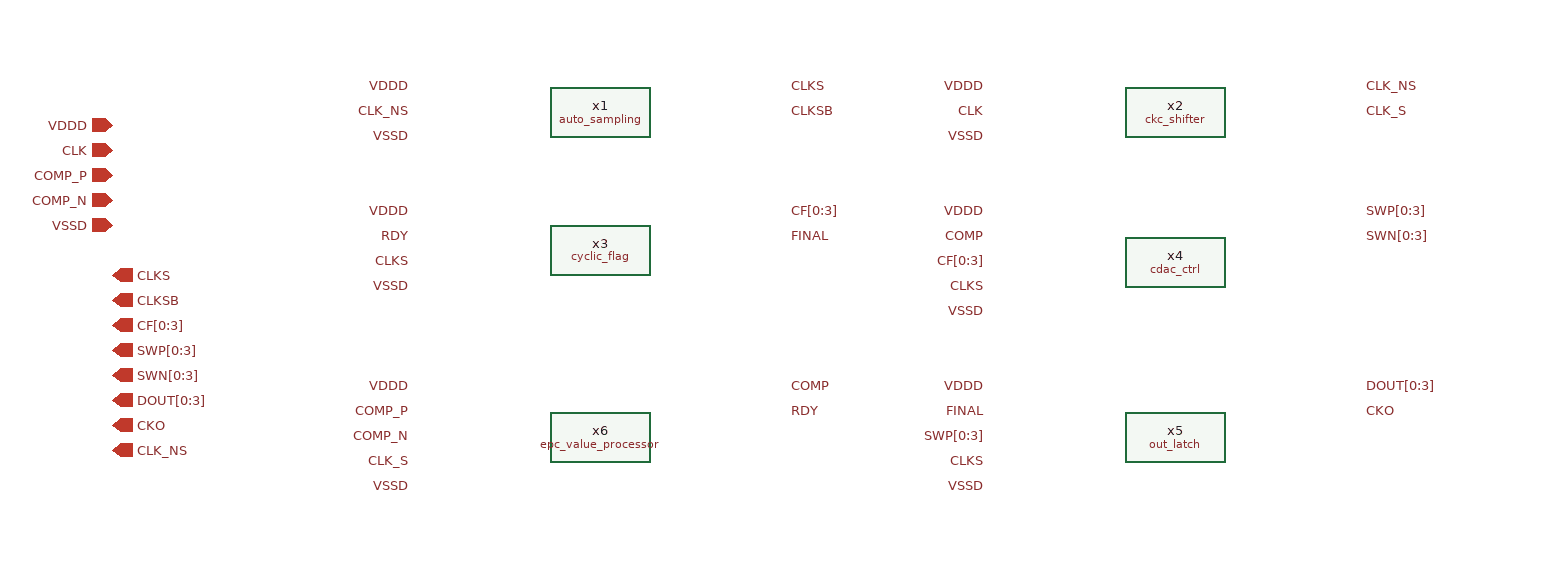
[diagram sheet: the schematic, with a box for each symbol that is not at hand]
v {xschem version=3.4.5 file_version=1.2
}
G {}
K {}
V {}
S {}
E {}
C {ckc_shifter.sym} 990 -390 0 0 {name=x2}
C {cyclic_flag.sym} 530 -280 0 0 {name=x3}
C {cdac_ctrl.sym} 990 -270 0 0 {name=x4}
C {out_latch.sym} 990 -130 0 0 {name=x5}
C {epc_value_processor.sym} 530 -130 0 0 {name=x6}
C {devices/ipin.sym} 140 -380 0 0 {name=p20 sig_type=std_logic lab=VDDD}
C {devices/ipin.sym} 140 -300 0 0 {name=p22 sig_type=std_logic lab=VSSD}
C {devices/lab_wire.sym} 380 -410 0 0 {name=p5 sig_type=std_logic lab=VDDD}
C {devices/lab_wire.sym} 380 -310 0 0 {name=p1 sig_type=std_logic lab=VDDD}
C {devices/lab_wire.sym} 380 -170 0 0 {name=p2 sig_type=std_logic lab=VDDD}
C {devices/lab_wire.sym} 840 -170 0 0 {name=p3 sig_type=std_logic lab=VDDD}
C {devices/lab_wire.sym} 840 -310 0 0 {name=p4 sig_type=std_logic lab=VDDD}
C {devices/lab_wire.sym} 840 -410 0 0 {name=p6 sig_type=std_logic lab=VDDD}
C {devices/lab_wire.sym} 380 -370 0 0 {name=p8 sig_type=std_logic lab=VSSD}
C {devices/lab_wire.sym} 380 -250 0 0 {name=p10 sig_type=std_logic lab=VSSD}
C {devices/lab_wire.sym} 380 -90 0 0 {name=p11 sig_type=std_logic lab=VSSD}
C {devices/lab_wire.sym} 840 -90 0 0 {name=p12 sig_type=std_logic lab=VSSD}
C {devices/lab_wire.sym} 840 -230 0 0 {name=p13 sig_type=std_logic lab=VSSD}
C {devices/lab_wire.sym} 840 -370 0 0 {name=p14 sig_type=std_logic lab=VSSD}
C {devices/lab_wire.sym} 380 -390 0 0 {name=p15 sig_type=std_logic lab=CLK_NS}
C {devices/lab_wire.sym} 1140 -410 0 1 {name=p16 sig_type=std_logic lab=CLK_NS}
C {devices/lab_wire.sym} 1140 -390 0 1 {name=p17 sig_type=std_logic lab=CLK_S}
C {devices/lab_wire.sym} 380 -110 0 0 {name=p18 sig_type=std_logic lab=CLK_S}
C {devices/lab_wire.sym} 840 -390 0 0 {name=p21 sig_type=std_logic lab=CLK}
C {devices/lab_wire.sym} 380 -150 0 0 {name=p25 sig_type=std_logic lab=COMP_P}
C {devices/lab_wire.sym} 380 -130 0 0 {name=p26 sig_type=std_logic lab=COMP_N}
C {devices/lab_wire.sym} 680 -170 0 1 {name=p27 sig_type=std_logic lab=COMP}
C {devices/lab_wire.sym} 680 -150 0 1 {name=p28 sig_type=std_logic lab=RDY}
C {devices/lab_wire.sym} 380 -290 0 0 {name=p29 sig_type=std_logic lab=RDY}
C {devices/lab_wire.sym} 380 -270 0 0 {name=p30 sig_type=std_logic lab=CLKS}
C {devices/lab_wire.sym} 680 -410 0 1 {name=p31 sig_type=std_logic lab=CLKS}
C {auto_sampling.sym} 530 -390 0 0 {name=x1}
C {devices/lab_wire.sym} 840 -250 0 0 {name=p32 sig_type=std_logic lab=CLKS}
C {devices/lab_wire.sym} 840 -110 0 0 {name=p33 sig_type=std_logic lab=CLKS}
C {devices/lab_wire.sym} 680 -290 0 1 {name=p34 sig_type=std_logic lab=FINAL}
C {devices/lab_wire.sym} 840 -150 0 0 {name=p35 sig_type=std_logic lab=FINAL}
C {devices/lab_wire.sym} 840 -290 0 0 {name=p36 sig_type=std_logic lab=COMP}
C {devices/lab_wire.sym} 680 -310 0 1 {name=p37 sig_type=std_logic lab=CF[0:3]}
C {devices/lab_wire.sym} 840 -270 0 0 {name=p38 sig_type=std_logic lab=CF[0:3]}
C {devices/lab_wire.sym} 1140 -310 0 1 {name=p39 sig_type=std_logic lab=SWP[0:3]}
C {devices/lab_wire.sym} 1140 -290 0 1 {name=p40 sig_type=std_logic lab=SWN[0:3]}
C {devices/lab_wire.sym} 840 -130 0 0 {name=p41 sig_type=std_logic lab=SWP[0:3]}
C {devices/lab_wire.sym} 1140 -170 0 1 {name=p42 sig_type=std_logic lab=DOUT[0:3]}
C {devices/lab_wire.sym} 1140 -150 0 1 {name=p43 sig_type=std_logic lab=CKO}
C {devices/ipin.sym} 140 -360 0 0 {name=p7 sig_type=std_logic lab=CLK}
C {devices/ipin.sym} 140 -340 0 0 {name=p9 sig_type=std_logic lab=COMP_P}
C {devices/ipin.sym} 140 -320 0 0 {name=p19 sig_type=std_logic lab=COMP_N}
C {devices/opin.sym} 140 -240 0 0 {name=p48 sig_type=std_logic lab=CLKSB}
C {devices/opin.sym} 140 -220 0 0 {name=p49 sig_type=std_logic lab=CF[0:3]}
C {devices/opin.sym} 140 -200 0 0 {name=p50 sig_type=std_logic lab=SWP[0:3]}
C {devices/opin.sym} 140 -180 0 0 {name=p51 sig_type=std_logic lab=SWN[0:3]}
C {devices/opin.sym} 140 -160 0 0 {name=p52 sig_type=std_logic lab=DOUT[0:3]}
C {devices/opin.sym} 140 -140 0 0 {name=p53 sig_type=std_logic lab=CKO}
C {devices/lab_wire.sym} 680 -390 0 1 {name=p23 sig_type=std_logic lab=CLKSB}
C {devices/opin.sym} 140 -260 0 0 {name=p24 sig_type=std_logic lab=CLKS}
C {devices/opin.sym} 140 -120 0 0 {name=p44 sig_type=std_logic lab=CLK_NS}
